VERSION 5.8 ;
BUSBITCHARS "[]" ;
DIVIDERCHAR "/" ;
UNITS
  DATABASE MICRONS 2000 ;
END UNITS

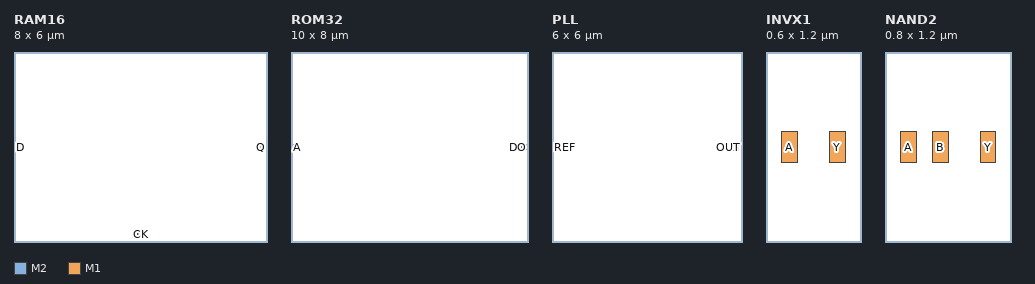
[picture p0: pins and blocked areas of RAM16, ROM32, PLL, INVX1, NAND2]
MACRO RAM16
  CLASS BLOCK ;
  ORIGIN 0 0 ;
  SIZE 8.0 BY 6.0 ;
  PIN D
    DIRECTION INPUT ;
    PORT
      LAYER M2 ;
      RECT 0.1 2.9 0.3 3.1 ;
    END
  END D
  PIN Q
    DIRECTION OUTPUT ;
    PORT
      LAYER M2 ;
      RECT 7.7 2.9 7.9 3.1 ;
    END
  END Q
  PIN CK
    DIRECTION INPUT ;
    PORT
      LAYER M2 ;
      RECT 3.9 0.1 4.1 0.3 ;
    END
  END CK
END RAM16

MACRO ROM32
  CLASS BLOCK ;
  SIZE 10.0 BY 8.0 ;
  PIN A
    DIRECTION INPUT ;
    PORT
      LAYER M2 ;
      RECT 0.1 3.9 0.3 4.1 ;
    END
  END A
  PIN DO
    DIRECTION OUTPUT ;
    PORT
      LAYER M2 ;
      RECT 9.7 3.9 9.9 4.1 ;
    END
  END DO
END ROM32

MACRO PLL
  CLASS BLOCK ;
  SIZE 6.0 BY 6.0 ;
  PIN REF
    DIRECTION INPUT ;
    PORT
      LAYER M2 ;
      RECT 0.1 2.9 0.3 3.1 ;
    END
  END REF
  PIN OUT
    DIRECTION OUTPUT ;
    PORT
      LAYER M2 ;
      RECT 5.7 2.9 5.9 3.1 ;
    END
  END OUT
END PLL

MACRO INVX1
  CLASS CORE ;
  SIZE 0.6 BY 1.2 ;
  PIN A
    DIRECTION INPUT ;
    PORT
      LAYER M1 ;
      RECT 0.1 0.5 0.2 0.7 ;
    END
  END A
  PIN Y
    DIRECTION OUTPUT ;
    PORT
      LAYER M1 ;
      RECT 0.4 0.5 0.5 0.7 ;
    END
  END Y
END INVX1

MACRO NAND2
  CLASS CORE ;
  SIZE 0.8 BY 1.2 ;
  PIN A
    DIRECTION INPUT ;
    PORT
      LAYER M1 ;
      RECT 0.1 0.5 0.2 0.7 ;
    END
  END A
  PIN B
    DIRECTION INPUT ;
    PORT
      LAYER M1 ;
      RECT 0.3 0.5 0.4 0.7 ;
    END
  END B
  PIN Y
    DIRECTION OUTPUT ;
    PORT
      LAYER M1 ;
      RECT 0.6 0.5 0.7 0.7 ;
    END
  END Y
END NAND2

END LIBRARY
